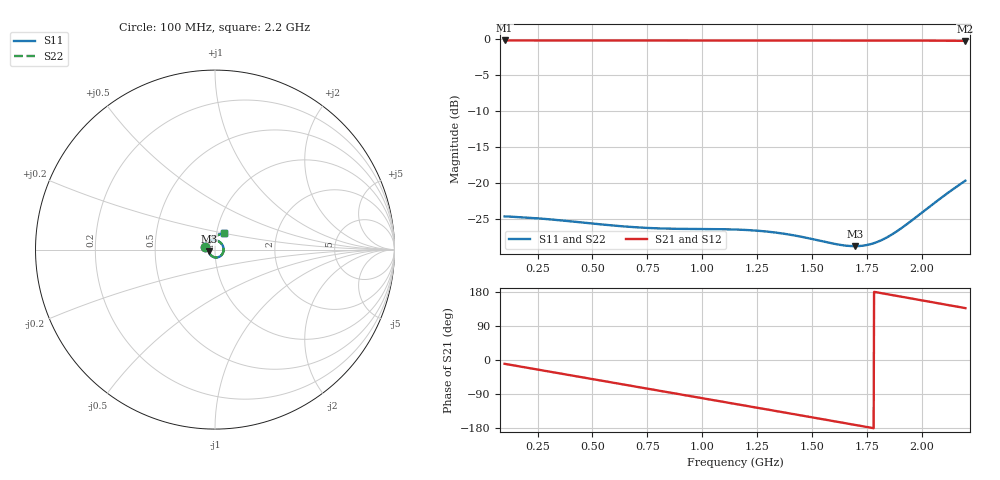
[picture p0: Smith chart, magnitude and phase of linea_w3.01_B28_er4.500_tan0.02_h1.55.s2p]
! Chirptenna · simulación 3D de una microstrip de dos puertos (S12 = S21, S22 = S11 por simetría)
# HZ S RI R 50
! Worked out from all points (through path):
!   1101 points, 100 MHz to 2.2 GHz, reference 50 ohm
!   highest |S21| = -0.15 dB at 100 MHz (marker M1); lowest = -0.2 dB at 2.2 GHz (marker M2)
!   group delay of S21, straight-line fit = 281 ps
!   lowest |S11| = -28.8 dB at 1.696 GHz (marker M3), VSWR 1.08, Z = 46.6 - j0.9 ohm
!   |S11| at or under -10 dB: start of sweep to end of sweep
!   |S22| runs from -28.8 to -19.7 dB; largest |S21 - S12| = 0
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1e8  -0.0563 0.0166  0.9678 -0.1715  0.9678 -0.1715  -0.0563 0.0166
1.820909e8  -0.0498 0.0293  0.9331 -0.3086  0.9331 -0.3086  -0.0498 0.0293
2.699091e8  -0.0396 0.0405  0.8746 -0.4481  0.8746 -0.4481  -0.0396 0.0405
3.596364e8  -0.0263 0.0484  0.7935 -0.5797  0.7935 -0.5797  -0.0263 0.0484
4.512727e8  -0.0108 0.0522  0.6904 -0.6992  0.6904 -0.6992  -0.0108 0.0522
6.307273e8  0.0195 0.0462  0.4396 -0.8784  0.4396 -0.8784  0.0195 0.0462
7.166364e8  0.0317 0.0376  0.3024 -0.9344  0.3024 -0.9344  0.0317 0.0376
8.006364e8  0.0407 0.0263  0.1617 -0.9685  0.1617 -0.9685  0.0407 0.0263
8.884545e8  0.0465 0.0124  0.0108 -0.9817  0.0108 -0.9817  0.0465 0.0124
9.743636e8  0.048 -0.00198  -0.1371 -0.9719  -0.1371 -0.9719  0.048 -0.00198
1.062182e9  0.0451 -0.0162  -0.285 -0.9391  -0.285 -0.9391  0.0451 -0.0162
1.15e9  0.038 -0.0286  -0.4262 -0.8838  -0.4262 -0.8838  0.038 -0.0286
1.318e9  0.0156 -0.0429  -0.6656 -0.7208  -0.6656 -0.7208  0.0156 -0.0429
1.411545e9  0.000477 -0.0435  -0.7753 -0.6015  -0.7753 -0.6015  0.000477 -0.0435
1.501273e9  -0.0137 -0.0385  -0.8608 -0.4713  -0.8608 -0.4713  -0.0137 -0.0385
1.600545e9  -0.027 -0.0266  -0.9302 -0.3131  -0.9302 -0.3131  -0.027 -0.0266
1.696e9  -0.0352 -0.00965  -0.9699 -0.1512  -0.9699 -0.1512  -0.0352 -0.00965
1.772364e9  -0.0372 0.0069  -0.9814 -0.0179  -0.9814 -0.0179  -0.0372 0.0069
1.850636e9  -0.0342 0.0255  -0.9742 0.1194  -0.9742 0.1194  -0.0342 0.0255
1.934636e9  -0.0246 0.0458  -0.9447 0.2644  -0.9447 0.2644  -0.0246 0.0458
2.018636e9  -0.00824 0.0647  -0.8933 0.4035  -0.8933 0.4035  -0.00824 0.0647
2.2e9  0.0489 0.0919  -0.7129 0.6676  -0.7129 0.6676  0.0489 0.0919
